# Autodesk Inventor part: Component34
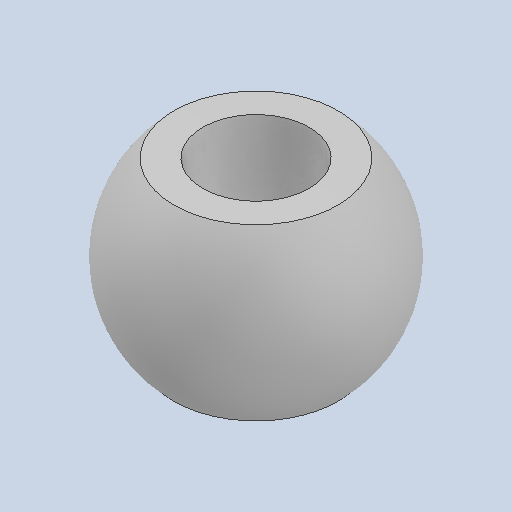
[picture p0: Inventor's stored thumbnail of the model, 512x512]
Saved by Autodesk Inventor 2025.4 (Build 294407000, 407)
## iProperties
Created: 2026-09
Part Number: Component34
Material: Generic
Document SubType Name: Modeling
Designer: AdminForWorker
Density: 1 g/cm^3
Appearance: Default
Title: Component34
Author: AdminForWorker
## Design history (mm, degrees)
feature "Body1"
body "Solid1"
